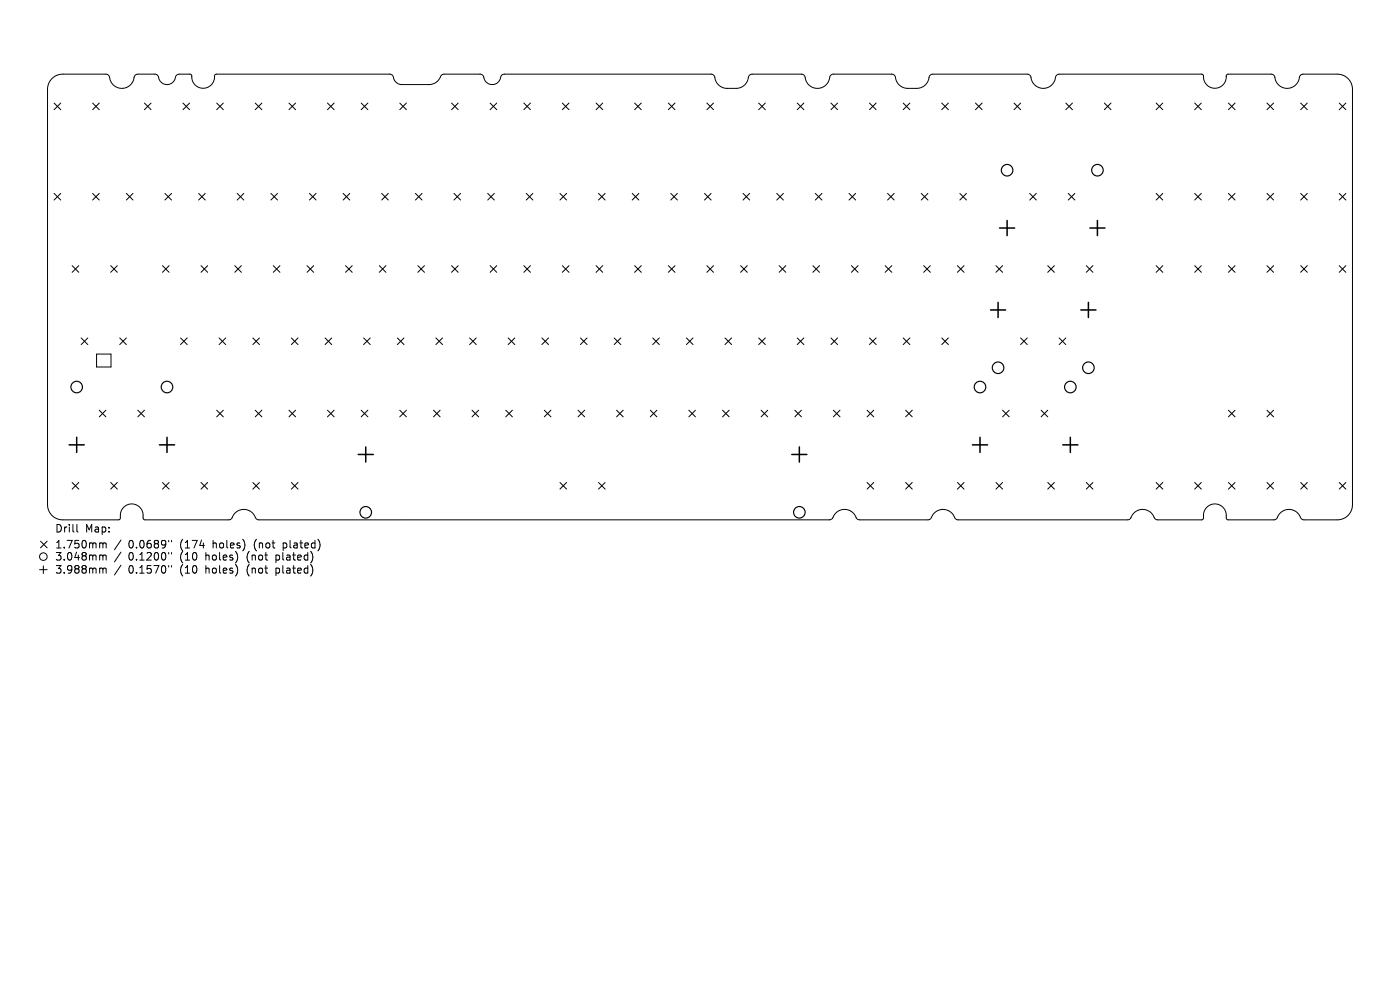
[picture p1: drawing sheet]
<svg xmlns="http://www.w3.org/2000/svg" width="297mm" height="210mm" viewBox="0 0 297 210" stroke-linecap="round" stroke-linejoin="round" font-family="sans-serif">
<defs><g id="words">
<g font-size="2.2">
<text x="11.6" y="113.2">Drill</text>
<text x="18.1" y="113.2">Map:</text>
<text x="11.6" y="116.6">1.750mm</text>
<text x="11.6" y="119.1">3.048mm</text>
<text x="27.3" y="116.6">0.0689&quot;</text>
<text x="27.3" y="119.1">0.1200&quot;</text>
<text x="38.3" y="116.6">(174</text>
<text x="38.3" y="119.1">(10</text>
<text x="43.8" y="119.1">holes)</text>
<text x="45.4" y="116.6">holes)</text>
<text x="52.7" y="119.1">(not</text>
<text x="54.3" y="116.6">(not</text>
<text x="59" y="119.1">plated)</text>
<text x="60.6" y="116.6">plated)</text>
<text x="11.6" y="121.9">3.988mm</text>
<text x="27.3" y="121.9">0.1570&quot;</text>
<text x="38.3" y="121.9">(10</text>
<text x="43.8" y="121.9">holes)</text>
<text x="52.7" y="121.9">(not</text>
<text x="59" y="121.9">plated)</text>
</g>
</g></defs>
<g fill="none" stroke="#000" stroke-width=".21">
<path d="M11.1 16.6a3.2 3.2 0 0 1 2.3-.9h9.1a.81 .81 0 0 1 .8 .7 2.66 2.66 0 0 0 2.7 2.3 2.66 2.66 0 0 0 2.5-2.6l.7-.4h3.7a1.03 1.03 0 0 1 .9 1.2 1.89 1.89 0 0 0 2.1 1 1.89 1.89 0 0 0 1.5-1.8l.6-.4h2.3l.3 .2a2.5 2.5 0 0 0 2.5 2.8 2.5 2.5 0 0 0 2.5-2.8l.3-.2h36.8a1.03 1.03 0 0 1 .9 1.2l.6 .7 .9 .3h6.1a3.5 3.5 0 0 0 2.6-2l.4-.2h7.6a1.03 1.03 0 0 1 1 1.2 1.88 1.88 0 0 0 2.1 1 1.88 1.88 0 0 0 1.4-1.8l.7-.4h43.8a.81 .81 0 0 1 .8 .7 2.62 2.62 0 0 0 2.6 2.3h2.2a2.94 2.94 0 0 0 2.5-2.6l.7-.4h10.4a.8 .8 0 0 1 .8 .7 2.66 2.66 0 0 0 2.8 2.3 2.66 2.66 0 0 0 2.5-2.6l.3-.3 .4-.1h12.4a.8 .8 0 0 1 .8 .7 2.62 2.62 0 0 0 2.6 2.3h2.1a2.94 2.94 0 0 0 2.5-2.6l.7-.4h20a.8 .8 0 0 1 .8 .7 2.66 2.66 0 0 0 2.8 2.3 2.66 2.66 0 0 0 2.5-2.6l.3-.3 .4-.1h30.2l.4 .2a2.5 2.5 0 0 0 2.5 2.8 2.5 2.5 0 0 0 2.4-2.8l.3-.2h9.2a.81 .81 0 0 1 .8 .7 2.67 2.67 0 0 0 2.8 2.3 2.67 2.67 0 0 0 2.5-2.6l.6-.4h7.3a3.2 3.2 0 0 1 3.2 3.2v88.2a3.2 3.2 0 0 1-3.2 3.2h-7.1l-.5-.3a2.74 2.74 0 0 0-2.7-1.9 2.74 2.74 0 0 0-2.6 1.9l-.6 .3h-9.7l-.2-.1-.2-.3a2.48 2.48 0 0 0-3-2.9 2.53 2.53 0 0 0-1.8 2.9l-.1 .3-.3 .1h-9.3l-.6-.3a2.74 2.74 0 0 0-2.6-1.9 2.74 2.74 0 0 0-2.6 1.9l-.6 .3h-35.9l-.6-.2a2.86 2.86 0 0 0-3.8-1.8l-.9 .7-.6 1-.5 .3h-14.5l-.5-.2a2.86 2.86 0 0 0-3.9-1.8l-.9 .7-.6 1-.5 .3h-121.1l-.5-.2a2.86 2.86 0 0 0-3.8-1.8l-.9 .7-.6 1-.5 .3h-17.8l-.3-.1-.1-.3a2.48 2.48 0 0 0-3.1-2.9 2.53 2.53 0 0 0-1.8 2.9l-.1 .3-.3 .1h-11.8a3.2 3.2 0 0 1-3.2-3.2v-88.2a3.2 3.2 0 0 1 1-2.3zM11.5 21.9l1.4 1.4M12.9 21.9l-1.4 1.4M19.7 21.9l1.4 1.4M21.1 21.9l-1.4 1.4M30.6 21.9l1.4 1.4M32 21.9l-1.4 1.4M38.8 21.9l1.4 1.4M40.2 21.9l-1.4 1.4M46 21.9l1.4 1.4M47.4 21.9l-1.4 1.4M54.1 21.9l1.5 1.4"/>
<path d="M55.6 21.9l-1.5 1.4M61.3 21.9l1.4 1.4M62.7 21.9l-1.4 1.4M69.5 21.9l1.4 1.4M70.9 21.9l-1.4 1.4M76.6 21.9l1.4 1.4M78 21.9l-1.4 1.4M84.8 21.9l1.4 1.4M86.2 21.9l-1.4 1.4M95.8 21.9l1.4 1.4M97.2 21.9l-1.4 1.4M104 21.9l1.4 1.4"/>
<path d="M105.4 21.9l-1.4 1.4M111.1 21.9l1.4 1.4M112.5 21.9l-1.4 1.4M119.3 21.9l1.4 1.4M120.7 21.9l-1.4 1.4M126.5 21.9l1.4 1.4M127.9 21.9l-1.4 1.4M134.6 21.9l1.4 1.4M136 21.9l-1.4 1.4M141.8 21.9l1.4 1.4M143.2 21.9l-1.4 1.4M150 21.9l1.4 1.4"/>
<path d="M151.4 21.9l-1.4 1.4M161 21.9l1.4 1.4M162.4 21.9l-1.4 1.4M169.1 21.9l1.4 1.4M170.5 21.9l-1.4 1.4M176.3 21.9l1.4 1.4M177.7 21.9l-1.4 1.4M184.5 21.9l1.4 1.4M185.9 21.9l-1.4 1.4M191.6 21.9l1.4 1.4M193 21.9l-1.4 1.4M199.8 21.9l1.4 1.4"/>
<path d="M201.2 21.9l-1.4 1.4M206.9 21.9l1.5 1.4M208.4 21.9l-1.5 1.4M215.1 21.9l1.4 1.4M216.5 21.9l-1.4 1.4M226.1 21.9l1.4 1.4M227.5 21.9l-1.4 1.4M234.3 21.9l1.4 1.4M235.7 21.9l-1.4 1.4M245.3 21.9l1.4 1.4M246.7 21.9l-1.4 1.4M253.4 21.9l1.5 1.4"/>
<path d="M254.9 21.9l-1.5 1.4M260.6 21.9l1.4 1.4M262 21.9l-1.4 1.4M268.8 21.9l1.4 1.4M270.2 21.9l-1.4 1.4M275.9 21.9l1.4 1.4M277.3 21.9l-1.4 1.4M284.1 21.9l1.4 1.4M285.5 21.9l-1.4 1.4M11.5 41l1.4 1.4M12.9 41l-1.4 1.4M15.3 56.4l1.4 1.4"/>
<path d="M16.7 56.4l-1.4 1.4M19.7 41l1.4 1.4M21.1 41l-1.4 1.4M23.5 56.4l1.4 1.4M24.9 56.4l-1.4 1.4M26.8 41l1.4 1.4M28.2 41l-1.4 1.4M34.5 56.4l1.4 1.4M35 41l1.4 1.4M35.9 56.4l-1.4 1.4M36.4 41l-1.4 1.4M42.1 41l1.4 1.4"/>
<path d="M42.6 56.4l1.5 1.4M43.5 41l-1.4 1.4M44.1 56.4l-1.5 1.4M49.8 56.4l1.4 1.4M50.3 41l1.4 1.4M51.2 56.4l-1.4 1.4M51.7 41l-1.4 1.4M57.5 41l1.4 1.4M58 56.4l1.4 1.4M58.9 41l-1.4 1.4M59.4 56.4l-1.4 1.4M65.1 56.4l1.4 1.4"/>
<path d="M65.6 41l1.5 1.4M66.5 56.4l-1.4 1.4M67.1 41l-1.5 1.4M72.8 41l1.4 1.4M73.3 56.4l1.4 1.4M74.2 41l-1.4 1.4M74.7 56.4l-1.4 1.4M80.5 56.4l1.4 1.4M81 41l1.4 1.4M81.9 56.4l-1.4 1.4M82.4 41l-1.4 1.4M88.1 41l1.4 1.4"/>
<path d="M88.6 56.4l1.4 1.4M89.5 41l-1.4 1.4M90 56.4l-1.4 1.4M95.8 56.4l1.4 1.4M96.3 41l1.4 1.4M97.2 56.4l-1.4 1.4M97.7 41l-1.4 1.4M103.5 41l1.4 1.4M104 56.4l1.4 1.4M104.9 41l-1.4 1.4M105.4 56.4l-1.4 1.4M111.1 56.4l1.4 1.4"/>
<path d="M111.6 41l1.4 1.4M112.5 56.4l-1.4 1.4M113 41l-1.4 1.4M118.8 41l1.4 1.4M119.3 56.4l1.4 1.4M120.2 41l-1.4 1.4M120.7 56.4l-1.4 1.4M126.5 56.4l1.4 1.4M127 41l1.4 1.4M127.9 56.4l-1.4 1.4M128.4 41l-1.4 1.4M134.1 41l1.4 1.4"/>
<path d="M134.6 56.4l1.4 1.4M135.5 41l-1.4 1.4M136 56.4l-1.4 1.4M141.8 56.4l1.4 1.4M142.3 41l1.4 1.4M143.2 56.4l-1.4 1.4M143.7 41l-1.4 1.4M149.5 41l1.4 1.4M150 56.4l1.4 1.4M150.9 41l-1.4 1.4M151.4 56.4l-1.4 1.4M157.1 56.4l1.4 1.4"/>
<path d="M157.6 41l1.4 1.4M158.5 56.4l-1.4 1.4M159 41l-1.4 1.4M164.8 41l1.4 1.4M165.3 56.4l1.4 1.4M166.2 41l-1.4 1.4M166.7 56.4l-1.4 1.4M172.4 56.4l1.5 1.4M173 41l1.4 1.4M173.9 56.4l-1.5 1.4M174.4 41l-1.4 1.4M180.1 41l1.4 1.4"/>
<path d="M180.6 56.4l1.4 1.4M181.5 41l-1.4 1.4M182 56.4l-1.4 1.4M187.8 56.4l1.4 1.4M188.3 41l1.4 1.4M189.2 56.4l-1.4 1.4M189.7 41l-1.4 1.4M195.4 41l1.5 1.4M196 56.4l1.4 1.4M196.9 41l-1.5 1.4M197.4 56.4l-1.4 1.4M203.1 56.4l1.4 1.4"/>
<path d="M203.6 41l1.4 1.4M204.5 56.4l-1.4 1.4M205 41l-1.4 1.4M211.3 56.4l1.4 1.4M212.7 56.4l-1.4 1.4M218.4 41l1.4 1.4M219.8 41l-1.4 1.4M222.3 56.4l1.4 1.4M223.7 56.4l-1.4 1.4M226.6 41l1.4 1.4M228 41l-1.4 1.4M230.5 56.4l1.4 1.4"/>
<path d="M231.9 56.4l-1.4 1.4M245.3 41l1.4 1.4M245.3 56.4l1.4 1.4M246.7 41l-1.4 1.4M246.7 56.4l-1.4 1.4M253.4 41l1.5 1.4M253.4 56.4l1.5 1.4M254.9 41l-1.5 1.4M254.9 56.4l-1.5 1.4M260.6 41l1.4 1.4M260.6 56.4l1.4 1.4M262 41l-1.4 1.4"/>
<path d="M262 56.4l-1.4 1.4M268.8 41l1.4 1.4M268.8 56.4l1.4 1.4M270.2 41l-1.4 1.4M270.2 56.4l-1.4 1.4M275.9 41l1.4 1.4M275.9 56.4l1.4 1.4M277.3 41l-1.4 1.4M277.3 56.4l-1.4 1.4M284.1 41l1.4 1.4M284.1 56.4l1.4 1.4M285.5 41l-1.4 1.4"/>
<path d="M285.5 56.4l-1.4 1.4M17.2 71.7l1.4 1.4M18.6 71.7l-1.4 1.4M20.5 75.1h3v2.7h-3zM25.4 71.7l1.4 1.4M26.8 71.7l-1.4 1.4M38.3 71.7l1.4 1.4M39.7 71.7l-1.4 1.4M46.5 71.7l1.4 1.4M47.9 71.7l-1.4 1.4M53.6 71.7l1.4 1.4M55 71.7l-1.4 1.4"/>
<path d="M61.8 71.7l1.4 1.4M63.2 71.7l-1.4 1.4M69 71.7l1.4 1.4M70.4 71.7l-1.4 1.4M77.1 71.7l1.5 1.4M78.6 71.7l-1.5 1.4M84.3 71.7l1.4 1.4M85.7 71.7l-1.4 1.4M92.5 71.7l1.4 1.4M93.9 71.7l-1.4 1.4M99.6 71.7l1.4 1.4M101 71.7l-1.4 1.4"/>
<path d="M107.8 71.7l1.4 1.4M109.2 71.7l-1.4 1.4M115 71.7l1.4 1.4M116.4 71.7l-1.4 1.4M123.1 71.7l1.4 1.4M124.5 71.7l-1.4 1.4M130.3 71.7l1.4 1.4M131.7 71.7l-1.4 1.4M138.5 71.7l1.4 1.4M139.9 71.7l-1.4 1.4M145.6 71.7l1.4 1.4M147 71.7l-1.4 1.4"/>
<path d="M153.8 71.7l1.4 1.4M155.2 71.7l-1.4 1.4M161 71.7l1.4 1.4M162.4 71.7l-1.4 1.4M169.1 71.7l1.4 1.4M170.5 71.7l-1.4 1.4M176.3 71.7l1.4 1.4M177.7 71.7l-1.4 1.4M184.5 71.7l1.4 1.4M185.9 71.7l-1.4 1.4M191.6 71.7l1.4 1.4M193 71.7l-1.4 1.4"/>
<path d="M199.8 71.7l1.4 1.4M201.2 71.7l-1.4 1.4M216.5 71.7l1.4 1.4M217.9 71.7l-1.4 1.4M224.7 71.7l1.4 1.4M226.1 71.7l-1.4 1.4M21.1 87l1.4 1.4M22.5 87l-1.4 1.4M29.2 87l1.4 1.4M30.6 87l-1.4 1.4M46 87l1.4 1.4M47.4 87l-1.4 1.4"/>
<path d="M54.1 87l1.5 1.4M55.6 87l-1.5 1.4M61.3 87l1.4 1.4M62.7 87l-1.4 1.4M69.5 87l1.4 1.4M70.9 87l-1.4 1.4M76.6 87l1.4 1.4M78 87l-1.4 1.4M84.8 87l1.4 1.4M86.2 87l-1.4 1.4M92 87l1.4 1.4M93.4 87l-1.4 1.4"/>
<path d="M100.1 87l1.4 1.4M101.5 87l-1.4 1.4M107.3 87l1.4 1.4M108.7 87l-1.4 1.4M115.5 87l1.4 1.4M116.9 87l-1.4 1.4M122.6 87l1.4 1.4M124 87l-1.4 1.4M130.8 87l1.4 1.4M132.2 87l-1.4 1.4M138 87l1.4 1.4M139.4 87l-1.4 1.4"/>
<path d="M146.1 87l1.4 1.4M147.5 87l-1.4 1.4M153.3 87l1.4 1.4M154.7 87l-1.4 1.4M161.5 87l1.4 1.4M162.9 87l-1.4 1.4M168.6 87l1.4 1.4M170 87l-1.4 1.4M176.8 87l1.4 1.4M178.2 87l-1.4 1.4M183.9 87l1.5 1.4M185.4 87l-1.5 1.4"/>
<path d="M192.1 87l1.4 1.4M193.5 87l-1.4 1.4M212.7 87l1.4 1.4M214.1 87l-1.4 1.4M220.9 87l1.4 1.4M222.3 87l-1.4 1.4M260.6 87l1.4 1.4M262 87l-1.4 1.4M268.8 87l1.4 1.4M270.2 87l-1.4 1.4M8.6 114.8l1.4 1.4M10 114.8l-1.4 1.4"/>
<path d="M15.3 102.3l1.4 1.5M16.3 111.3v1.3l.2 .3M16.7 102.3l-1.4 1.5M21.4 115.2l.4 .2M21.4 117.7l.4 .3M21.8 115.4l.3-.2h.3l.1 1M21.8 115.4v.8M21.8 118v.8M21.8 118l.3-.3 .3 .1 .1 1M23.5 102.3l1.4 1.5M24.9 102.3l-1.4 1.5M25.7 114.6l-1.4 2"/>
<path d="M25.7 117.1l-1.4 2.1M25.7 119.9l-1.4 2.1M34.5 102.3l1.4 1.5M35.8 114.6v.3M35.8 117.2v.3M35.8 120v.3M35.9 102.3l-1.4 1.5M36.4 114.6v.3M36.4 117.2v.3M36.4 120v.3M42.6 102.3l1.5 1.5M44.1 102.3l-1.5 1.5"/>
<path d="M53.6 102.3l1.4 1.5M55 102.3l-1.4 1.5M61.8 102.3l1.4 1.5M63.2 102.3l-1.4 1.5M118.8 102.3l1.4 1.5M120.2 102.3l-1.4 1.5M127 102.3l1.4 1.5M128.4 102.3l-1.4 1.5M183.9 102.3l1.5 1.5M185.4 102.3l-1.5 1.5M192.1 102.3l1.4 1.5M193.5 102.3l-1.4 1.5"/>
<path d="M203.1 102.3l1.4 1.5M204.5 102.3l-1.4 1.5M211.3 102.3l1.4 1.5M212.7 102.3l-1.4 1.5M222.3 102.3l1.4 1.5M223.7 102.3l-1.4 1.5M230.5 102.3l1.4 1.5M231.9 102.3l-1.4 1.5M245.3 102.3l1.4 1.5M246.7 102.3l-1.4 1.5M253.4 102.3l1.5 1.5M254.9 102.3l-1.5 1.5"/>
<path d="M260.6 102.3l1.4 1.5M262 102.3l-1.4 1.5M268.8 102.3l1.4 1.5M270.2 102.3l-1.4 1.5M275.9 102.3l1.4 1.5M277.3 102.3l-1.4 1.5M284.1 102.3l1.4 1.5M285.5 102.3l-1.4 1.5M8.4 120.8h1.6M9.2 120v1.7M21.4 120.5l.4 .2M21.8 120.7v.9"/>
<path d="M21.8 120.7l.3-.2 .3 .1 .1 1"/>
<circle cx="9.2" cy="118.1" r=".8"/>
</g>
<g fill="none" stroke="#000" stroke-width=".25">
<circle cx="213.7" cy="36.1" r="1.23"/>
<circle cx="232.8" cy="36.1" r="1.23"/>
<circle cx="211.7" cy="78" r="1.23"/>
<circle cx="230.9" cy="78" r="1.23"/>
<circle cx="16.3" cy="82.1" r="1.23"/>
<circle cx="35.4" cy="82.1" r="1.23"/>
<circle cx="207.9" cy="82.1" r="1.23"/>
<circle cx="227.1" cy="82.1" r="1.23"/>
<circle cx="77.6" cy="108.7" r="1.23"/>
<circle cx="169.6" cy="108.7" r="1.23"/>
</g>
<g fill="none" stroke="#000" stroke-width=".32">
<path d="M212 48.4h3.3M213.7 46.8v3.2M231.2 48.4h3.2M232.8 46.8v3.2M210.1 65.7h3.2M211.7 64.1v3.3M229.3 65.7h3.2M230.9 64.1v3.3M14.7 94.4h3.2M16.3 92.8v3.2M33.8 94.4h3.2M35.4 92.8v3.2"/>
<path d="M76 96.4h3.2M77.6 94.8v3.2M168 96.4h3.2M169.6 94.8v3.2M206.3 94.4h3.2M207.9 92.8v3.2M225.5 94.4h3.2M227.1 92.8v3.2"/>
</g>
<use href="#words"/>
</svg>
